VERSION 5.8 ;
BUSBITCHARS "[]" ;
DIVIDERCHAR "/" ;
UNITS
    DATABASE MICRONS 1000 ;
END UNITS

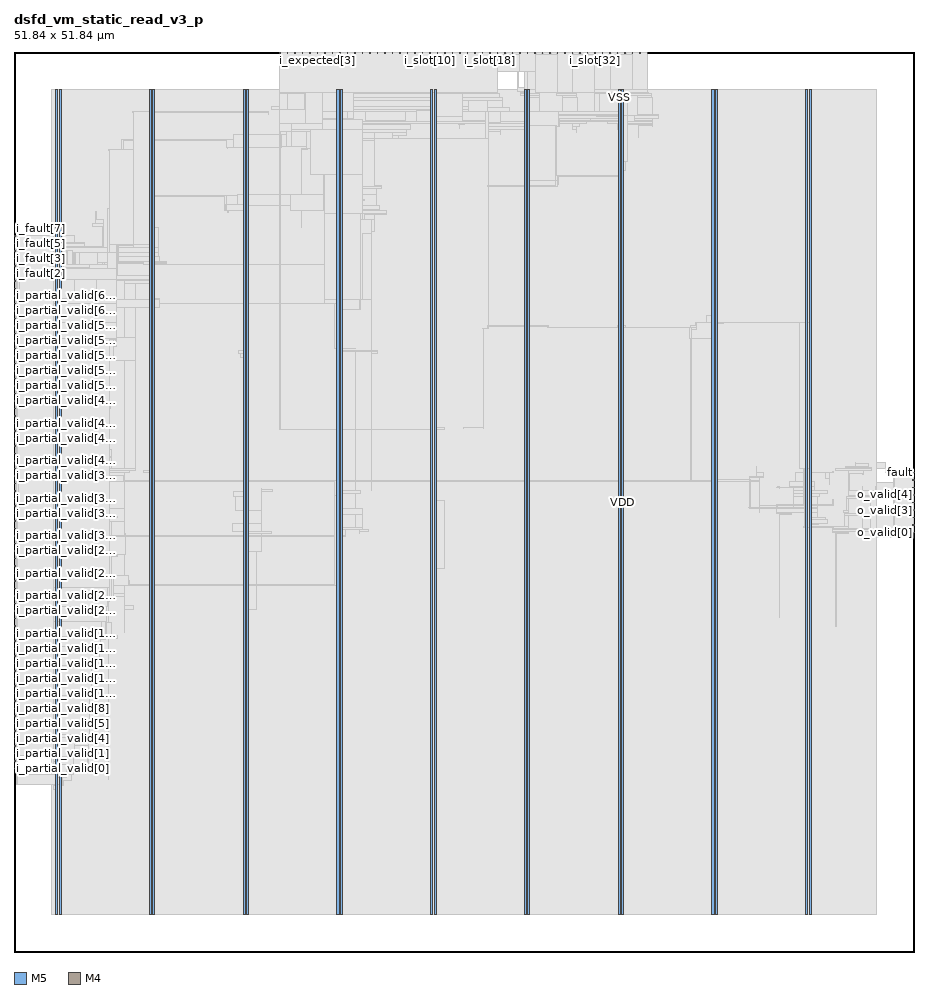
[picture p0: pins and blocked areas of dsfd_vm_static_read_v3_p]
MACRO dsfd_vm_static_read_v3_p
  FOREIGN dsfd_vm_static_read_v3_p 0 0 ;
  CLASS BLOCK ;
  SIZE 51.84 BY 51.84 ;
  PIN ck
    DIRECTION INPUT ;
    USE SIGNAL ;
    PORT
      LAYER M5 ;
        RECT  15.312 51.756 15.336 51.84 ;
    END
  END ck
  PIN fault
    DIRECTION OUTPUT ;
    USE SIGNAL ;
    PORT
      LAYER M4 ;
        RECT  51.756 27.6 51.84 27.624 ;
    END
  END fault
  PIN i_expected[0]
    DIRECTION INPUT ;
    USE SIGNAL ;
    PORT
      LAYER M5 ;
        RECT  16.176 51.756 16.2 51.84 ;
    END
  END i_expected[0]
  PIN i_expected[1]
    DIRECTION INPUT ;
    USE SIGNAL ;
    PORT
      LAYER M5 ;
        RECT  16.608 51.756 16.632 51.84 ;
    END
  END i_expected[1]
  PIN i_expected[2]
    DIRECTION INPUT ;
    USE SIGNAL ;
    PORT
      LAYER M5 ;
        RECT  17.04 51.756 17.064 51.84 ;
    END
  END i_expected[2]
  PIN i_expected[3]
    DIRECTION INPUT ;
    USE SIGNAL ;
    PORT
      LAYER M5 ;
        RECT  17.472 51.756 17.496 51.84 ;
    END
  END i_expected[3]
  PIN i_expected[4]
    DIRECTION INPUT ;
    USE SIGNAL ;
    PORT
      LAYER M5 ;
        RECT  17.904 51.756 17.928 51.84 ;
    END
  END i_expected[4]
  PIN i_expected[5]
    DIRECTION INPUT ;
    USE SIGNAL ;
    PORT
      LAYER M5 ;
        RECT  18.336 51.756 18.36 51.84 ;
    END
  END i_expected[5]
  PIN i_expected[6]
    DIRECTION INPUT ;
    USE SIGNAL ;
    PORT
      LAYER M5 ;
        RECT  18.768 51.756 18.792 51.84 ;
    END
  END i_expected[6]
  PIN i_expected[7]
    DIRECTION INPUT ;
    USE SIGNAL ;
    PORT
      LAYER M5 ;
        RECT  19.2 51.756 19.224 51.84 ;
    END
  END i_expected[7]
  PIN i_fault[0]
    DIRECTION INPUT ;
    USE SIGNAL ;
    PORT
      LAYER M4 ;
        RECT  0 38.208 0.084 38.232 ;
    END
  END i_fault[0]
  PIN i_fault[1]
    DIRECTION INPUT ;
    USE SIGNAL ;
    PORT
      LAYER M4 ;
        RECT  0 38.64 0.084 38.664 ;
    END
  END i_fault[1]
  PIN i_fault[2]
    DIRECTION INPUT ;
    USE SIGNAL ;
    PORT
      LAYER M4 ;
        RECT  0 39.072 0.084 39.096 ;
    END
  END i_fault[2]
  PIN i_fault[3]
    DIRECTION INPUT ;
    USE SIGNAL ;
    PORT
      LAYER M4 ;
        RECT  0 39.504 0.084 39.528 ;
    END
  END i_fault[3]
  PIN i_fault[4]
    DIRECTION INPUT ;
    USE SIGNAL ;
    PORT
      LAYER M4 ;
        RECT  0 39.936 0.084 39.96 ;
    END
  END i_fault[4]
  PIN i_fault[5]
    DIRECTION INPUT ;
    USE SIGNAL ;
    PORT
      LAYER M4 ;
        RECT  0 40.368 0.084 40.392 ;
    END
  END i_fault[5]
  PIN i_fault[6]
    DIRECTION INPUT ;
    USE SIGNAL ;
    PORT
      LAYER M4 ;
        RECT  0 40.8 0.084 40.824 ;
    END
  END i_fault[6]
  PIN i_fault[7]
    DIRECTION INPUT ;
    USE SIGNAL ;
    PORT
      LAYER M4 ;
        RECT  0 41.232 0.084 41.256 ;
    END
  END i_fault[7]
  PIN i_partial_valid[0]
    DIRECTION INPUT ;
    USE SIGNAL ;
    PORT
      LAYER M4 ;
        RECT  0 10.56 0.084 10.584 ;
    END
  END i_partial_valid[0]
  PIN i_partial_valid[10]
    DIRECTION INPUT ;
    USE SIGNAL ;
    PORT
      LAYER M4 ;
        RECT  0 14.88 0.084 14.904 ;
    END
  END i_partial_valid[10]
  PIN i_partial_valid[11]
    DIRECTION INPUT ;
    USE SIGNAL ;
    PORT
      LAYER M4 ;
        RECT  0 15.312 0.084 15.336 ;
    END
  END i_partial_valid[11]
  PIN i_partial_valid[12]
    DIRECTION INPUT ;
    USE SIGNAL ;
    PORT
      LAYER M4 ;
        RECT  0 15.744 0.084 15.768 ;
    END
  END i_partial_valid[12]
  PIN i_partial_valid[13]
    DIRECTION INPUT ;
    USE SIGNAL ;
    PORT
      LAYER M4 ;
        RECT  0 16.176 0.084 16.2 ;
    END
  END i_partial_valid[13]
  PIN i_partial_valid[14]
    DIRECTION INPUT ;
    USE SIGNAL ;
    PORT
      LAYER M4 ;
        RECT  0 16.608 0.084 16.632 ;
    END
  END i_partial_valid[14]
  PIN i_partial_valid[15]
    DIRECTION INPUT ;
    USE SIGNAL ;
    PORT
      LAYER M4 ;
        RECT  0 17.04 0.084 17.064 ;
    END
  END i_partial_valid[15]
  PIN i_partial_valid[16]
    DIRECTION INPUT ;
    USE SIGNAL ;
    PORT
      LAYER M4 ;
        RECT  0 17.472 0.084 17.496 ;
    END
  END i_partial_valid[16]
  PIN i_partial_valid[17]
    DIRECTION INPUT ;
    USE SIGNAL ;
    PORT
      LAYER M4 ;
        RECT  0 17.904 0.084 17.928 ;
    END
  END i_partial_valid[17]
  PIN i_partial_valid[18]
    DIRECTION INPUT ;
    USE SIGNAL ;
    PORT
      LAYER M4 ;
        RECT  0 18.336 0.084 18.36 ;
    END
  END i_partial_valid[18]
  PIN i_partial_valid[19]
    DIRECTION INPUT ;
    USE SIGNAL ;
    PORT
      LAYER M4 ;
        RECT  0 18.768 0.084 18.792 ;
    END
  END i_partial_valid[19]
  PIN i_partial_valid[1]
    DIRECTION INPUT ;
    USE SIGNAL ;
    PORT
      LAYER M4 ;
        RECT  0 10.992 0.084 11.016 ;
    END
  END i_partial_valid[1]
  PIN i_partial_valid[20]
    DIRECTION INPUT ;
    USE SIGNAL ;
    PORT
      LAYER M4 ;
        RECT  0 19.2 0.084 19.224 ;
    END
  END i_partial_valid[20]
  PIN i_partial_valid[21]
    DIRECTION INPUT ;
    USE SIGNAL ;
    PORT
      LAYER M4 ;
        RECT  0 19.632 0.084 19.656 ;
    END
  END i_partial_valid[21]
  PIN i_partial_valid[22]
    DIRECTION INPUT ;
    USE SIGNAL ;
    PORT
      LAYER M4 ;
        RECT  0 20.064 0.084 20.088 ;
    END
  END i_partial_valid[22]
  PIN i_partial_valid[23]
    DIRECTION INPUT ;
    USE SIGNAL ;
    PORT
      LAYER M4 ;
        RECT  0 20.496 0.084 20.52 ;
    END
  END i_partial_valid[23]
  PIN i_partial_valid[24]
    DIRECTION INPUT ;
    USE SIGNAL ;
    PORT
      LAYER M4 ;
        RECT  0 20.928 0.084 20.952 ;
    END
  END i_partial_valid[24]
  PIN i_partial_valid[25]
    DIRECTION INPUT ;
    USE SIGNAL ;
    PORT
      LAYER M4 ;
        RECT  0 21.36 0.084 21.384 ;
    END
  END i_partial_valid[25]
  PIN i_partial_valid[26]
    DIRECTION INPUT ;
    USE SIGNAL ;
    PORT
      LAYER M4 ;
        RECT  0 21.792 0.084 21.816 ;
    END
  END i_partial_valid[26]
  PIN i_partial_valid[27]
    DIRECTION INPUT ;
    USE SIGNAL ;
    PORT
      LAYER M4 ;
        RECT  0 22.224 0.084 22.248 ;
    END
  END i_partial_valid[27]
  PIN i_partial_valid[28]
    DIRECTION INPUT ;
    USE SIGNAL ;
    PORT
      LAYER M4 ;
        RECT  0 22.656 0.084 22.68 ;
    END
  END i_partial_valid[28]
  PIN i_partial_valid[29]
    DIRECTION INPUT ;
    USE SIGNAL ;
    PORT
      LAYER M4 ;
        RECT  0 23.088 0.084 23.112 ;
    END
  END i_partial_valid[29]
  PIN i_partial_valid[2]
    DIRECTION INPUT ;
    USE SIGNAL ;
    PORT
      LAYER M4 ;
        RECT  0 11.424 0.084 11.448 ;
    END
  END i_partial_valid[2]
  PIN i_partial_valid[30]
    DIRECTION INPUT ;
    USE SIGNAL ;
    PORT
      LAYER M4 ;
        RECT  0 23.52 0.084 23.544 ;
    END
  END i_partial_valid[30]
  PIN i_partial_valid[31]
    DIRECTION INPUT ;
    USE SIGNAL ;
    PORT
      LAYER M4 ;
        RECT  0 23.952 0.084 23.976 ;
    END
  END i_partial_valid[31]
  PIN i_partial_valid[32]
    DIRECTION INPUT ;
    USE SIGNAL ;
    PORT
      LAYER M4 ;
        RECT  0 24.384 0.084 24.408 ;
    END
  END i_partial_valid[32]
  PIN i_partial_valid[33]
    DIRECTION INPUT ;
    USE SIGNAL ;
    PORT
      LAYER M4 ;
        RECT  0 24.816 0.084 24.84 ;
    END
  END i_partial_valid[33]
  PIN i_partial_valid[34]
    DIRECTION INPUT ;
    USE SIGNAL ;
    PORT
      LAYER M4 ;
        RECT  0 25.248 0.084 25.272 ;
    END
  END i_partial_valid[34]
  PIN i_partial_valid[35]
    DIRECTION INPUT ;
    USE SIGNAL ;
    PORT
      LAYER M4 ;
        RECT  0 25.68 0.084 25.704 ;
    END
  END i_partial_valid[35]
  PIN i_partial_valid[36]
    DIRECTION INPUT ;
    USE SIGNAL ;
    PORT
      LAYER M4 ;
        RECT  0 26.112 0.084 26.136 ;
    END
  END i_partial_valid[36]
  PIN i_partial_valid[37]
    DIRECTION INPUT ;
    USE SIGNAL ;
    PORT
      LAYER M4 ;
        RECT  0 26.544 0.084 26.568 ;
    END
  END i_partial_valid[37]
  PIN i_partial_valid[38]
    DIRECTION INPUT ;
    USE SIGNAL ;
    PORT
      LAYER M4 ;
        RECT  0 26.976 0.084 27 ;
    END
  END i_partial_valid[38]
  PIN i_partial_valid[39]
    DIRECTION INPUT ;
    USE SIGNAL ;
    PORT
      LAYER M4 ;
        RECT  0 27.408 0.084 27.432 ;
    END
  END i_partial_valid[39]
  PIN i_partial_valid[3]
    DIRECTION INPUT ;
    USE SIGNAL ;
    PORT
      LAYER M4 ;
        RECT  0 11.856 0.084 11.88 ;
    END
  END i_partial_valid[3]
  PIN i_partial_valid[40]
    DIRECTION INPUT ;
    USE SIGNAL ;
    PORT
      LAYER M4 ;
        RECT  0 27.84 0.084 27.864 ;
    END
  END i_partial_valid[40]
  PIN i_partial_valid[41]
    DIRECTION INPUT ;
    USE SIGNAL ;
    PORT
      LAYER M4 ;
        RECT  0 28.272 0.084 28.296 ;
    END
  END i_partial_valid[41]
  PIN i_partial_valid[42]
    DIRECTION INPUT ;
    USE SIGNAL ;
    PORT
      LAYER M4 ;
        RECT  0 28.704 0.084 28.728 ;
    END
  END i_partial_valid[42]
  PIN i_partial_valid[43]
    DIRECTION INPUT ;
    USE SIGNAL ;
    PORT
      LAYER M4 ;
        RECT  0 29.136 0.084 29.16 ;
    END
  END i_partial_valid[43]
  PIN i_partial_valid[44]
    DIRECTION INPUT ;
    USE SIGNAL ;
    PORT
      LAYER M4 ;
        RECT  0 29.568 0.084 29.592 ;
    END
  END i_partial_valid[44]
  PIN i_partial_valid[45]
    DIRECTION INPUT ;
    USE SIGNAL ;
    PORT
      LAYER M4 ;
        RECT  0 30 0.084 30.024 ;
    END
  END i_partial_valid[45]
  PIN i_partial_valid[46]
    DIRECTION INPUT ;
    USE SIGNAL ;
    PORT
      LAYER M4 ;
        RECT  0 30.432 0.084 30.456 ;
    END
  END i_partial_valid[46]
  PIN i_partial_valid[47]
    DIRECTION INPUT ;
    USE SIGNAL ;
    PORT
      LAYER M4 ;
        RECT  0 30.864 0.084 30.888 ;
    END
  END i_partial_valid[47]
  PIN i_partial_valid[48]
    DIRECTION INPUT ;
    USE SIGNAL ;
    PORT
      LAYER M4 ;
        RECT  0 31.296 0.084 31.32 ;
    END
  END i_partial_valid[48]
  PIN i_partial_valid[49]
    DIRECTION INPUT ;
    USE SIGNAL ;
    PORT
      LAYER M4 ;
        RECT  0 31.728 0.084 31.752 ;
    END
  END i_partial_valid[49]
  PIN i_partial_valid[4]
    DIRECTION INPUT ;
    USE SIGNAL ;
    PORT
      LAYER M4 ;
        RECT  0 12.288 0.084 12.312 ;
    END
  END i_partial_valid[4]
  PIN i_partial_valid[50]
    DIRECTION INPUT ;
    USE SIGNAL ;
    PORT
      LAYER M4 ;
        RECT  0 32.16 0.084 32.184 ;
    END
  END i_partial_valid[50]
  PIN i_partial_valid[51]
    DIRECTION INPUT ;
    USE SIGNAL ;
    PORT
      LAYER M4 ;
        RECT  0 32.592 0.084 32.616 ;
    END
  END i_partial_valid[51]
  PIN i_partial_valid[52]
    DIRECTION INPUT ;
    USE SIGNAL ;
    PORT
      LAYER M4 ;
        RECT  0 33.024 0.084 33.048 ;
    END
  END i_partial_valid[52]
  PIN i_partial_valid[53]
    DIRECTION INPUT ;
    USE SIGNAL ;
    PORT
      LAYER M4 ;
        RECT  0 33.456 0.084 33.48 ;
    END
  END i_partial_valid[53]
  PIN i_partial_valid[54]
    DIRECTION INPUT ;
    USE SIGNAL ;
    PORT
      LAYER M4 ;
        RECT  0 33.888 0.084 33.912 ;
    END
  END i_partial_valid[54]
  PIN i_partial_valid[55]
    DIRECTION INPUT ;
    USE SIGNAL ;
    PORT
      LAYER M4 ;
        RECT  0 34.32 0.084 34.344 ;
    END
  END i_partial_valid[55]
  PIN i_partial_valid[56]
    DIRECTION INPUT ;
    USE SIGNAL ;
    PORT
      LAYER M4 ;
        RECT  0 34.752 0.084 34.776 ;
    END
  END i_partial_valid[56]
  PIN i_partial_valid[57]
    DIRECTION INPUT ;
    USE SIGNAL ;
    PORT
      LAYER M4 ;
        RECT  0 35.184 0.084 35.208 ;
    END
  END i_partial_valid[57]
  PIN i_partial_valid[58]
    DIRECTION INPUT ;
    USE SIGNAL ;
    PORT
      LAYER M4 ;
        RECT  0 35.616 0.084 35.64 ;
    END
  END i_partial_valid[58]
  PIN i_partial_valid[59]
    DIRECTION INPUT ;
    USE SIGNAL ;
    PORT
      LAYER M4 ;
        RECT  0 36.048 0.084 36.072 ;
    END
  END i_partial_valid[59]
  PIN i_partial_valid[5]
    DIRECTION INPUT ;
    USE SIGNAL ;
    PORT
      LAYER M4 ;
        RECT  0 12.72 0.084 12.744 ;
    END
  END i_partial_valid[5]
  PIN i_partial_valid[60]
    DIRECTION INPUT ;
    USE SIGNAL ;
    PORT
      LAYER M4 ;
        RECT  0 36.48 0.084 36.504 ;
    END
  END i_partial_valid[60]
  PIN i_partial_valid[61]
    DIRECTION INPUT ;
    USE SIGNAL ;
    PORT
      LAYER M4 ;
        RECT  0 36.912 0.084 36.936 ;
    END
  END i_partial_valid[61]
  PIN i_partial_valid[62]
    DIRECTION INPUT ;
    USE SIGNAL ;
    PORT
      LAYER M4 ;
        RECT  0 37.344 0.084 37.368 ;
    END
  END i_partial_valid[62]
  PIN i_partial_valid[63]
    DIRECTION INPUT ;
    USE SIGNAL ;
    PORT
      LAYER M4 ;
        RECT  0 37.776 0.084 37.8 ;
    END
  END i_partial_valid[63]
  PIN i_partial_valid[6]
    DIRECTION INPUT ;
    USE SIGNAL ;
    PORT
      LAYER M4 ;
        RECT  0 13.152 0.084 13.176 ;
    END
  END i_partial_valid[6]
  PIN i_partial_valid[7]
    DIRECTION INPUT ;
    USE SIGNAL ;
    PORT
      LAYER M4 ;
        RECT  0 13.584 0.084 13.608 ;
    END
  END i_partial_valid[7]
  PIN i_partial_valid[8]
    DIRECTION INPUT ;
    USE SIGNAL ;
    PORT
      LAYER M4 ;
        RECT  0 14.016 0.084 14.04 ;
    END
  END i_partial_valid[8]
  PIN i_partial_valid[9]
    DIRECTION INPUT ;
    USE SIGNAL ;
    PORT
      LAYER M4 ;
        RECT  0 14.448 0.084 14.472 ;
    END
  END i_partial_valid[9]
  PIN i_slot[0]
    DIRECTION INPUT ;
    USE SIGNAL ;
    PORT
      LAYER M5 ;
        RECT  19.632 51.756 19.656 51.84 ;
    END
  END i_slot[0]
  PIN i_slot[10]
    DIRECTION INPUT ;
    USE SIGNAL ;
    PORT
      LAYER M5 ;
        RECT  23.952 51.756 23.976 51.84 ;
    END
  END i_slot[10]
  PIN i_slot[11]
    DIRECTION INPUT ;
    USE SIGNAL ;
    PORT
      LAYER M5 ;
        RECT  24.384 51.756 24.408 51.84 ;
    END
  END i_slot[11]
  PIN i_slot[12]
    DIRECTION INPUT ;
    USE SIGNAL ;
    PORT
      LAYER M5 ;
        RECT  24.816 51.756 24.84 51.84 ;
    END
  END i_slot[12]
  PIN i_slot[13]
    DIRECTION INPUT ;
    USE SIGNAL ;
    PORT
      LAYER M5 ;
        RECT  25.248 51.756 25.272 51.84 ;
    END
  END i_slot[13]
  PIN i_slot[14]
    DIRECTION INPUT ;
    USE SIGNAL ;
    PORT
      LAYER M5 ;
        RECT  25.68 51.756 25.704 51.84 ;
    END
  END i_slot[14]
  PIN i_slot[15]
    DIRECTION INPUT ;
    USE SIGNAL ;
    PORT
      LAYER M5 ;
        RECT  26.112 51.756 26.136 51.84 ;
    END
  END i_slot[15]
  PIN i_slot[16]
    DIRECTION INPUT ;
    USE SIGNAL ;
    PORT
      LAYER M5 ;
        RECT  26.544 51.756 26.568 51.84 ;
    END
  END i_slot[16]
  PIN i_slot[17]
    DIRECTION INPUT ;
    USE SIGNAL ;
    PORT
      LAYER M5 ;
        RECT  26.976 51.756 27 51.84 ;
    END
  END i_slot[17]
  PIN i_slot[18]
    DIRECTION INPUT ;
    USE SIGNAL ;
    PORT
      LAYER M5 ;
        RECT  27.408 51.756 27.432 51.84 ;
    END
  END i_slot[18]
  PIN i_slot[19]
    DIRECTION INPUT ;
    USE SIGNAL ;
    PORT
      LAYER M5 ;
        RECT  27.84 51.756 27.864 51.84 ;
    END
  END i_slot[19]
  PIN i_slot[1]
    DIRECTION INPUT ;
    USE SIGNAL ;
    PORT
      LAYER M5 ;
        RECT  20.064 51.756 20.088 51.84 ;
    END
  END i_slot[1]
  PIN i_slot[20]
    DIRECTION INPUT ;
    USE SIGNAL ;
    PORT
      LAYER M5 ;
        RECT  28.272 51.756 28.296 51.84 ;
    END
  END i_slot[20]
  PIN i_slot[21]
    DIRECTION INPUT ;
    USE SIGNAL ;
    PORT
      LAYER M5 ;
        RECT  28.704 51.756 28.728 51.84 ;
    END
  END i_slot[21]
  PIN i_slot[22]
    DIRECTION INPUT ;
    USE SIGNAL ;
    PORT
      LAYER M5 ;
        RECT  29.136 51.756 29.16 51.84 ;
    END
  END i_slot[22]
  PIN i_slot[23]
    DIRECTION INPUT ;
    USE SIGNAL ;
    PORT
      LAYER M5 ;
        RECT  29.568 51.756 29.592 51.84 ;
    END
  END i_slot[23]
  PIN i_slot[24]
    DIRECTION INPUT ;
    USE SIGNAL ;
    PORT
      LAYER M5 ;
        RECT  30 51.756 30.024 51.84 ;
    END
  END i_slot[24]
  PIN i_slot[25]
    DIRECTION INPUT ;
    USE SIGNAL ;
    PORT
      LAYER M5 ;
        RECT  30.432 51.756 30.456 51.84 ;
    END
  END i_slot[25]
  PIN i_slot[26]
    DIRECTION INPUT ;
    USE SIGNAL ;
    PORT
      LAYER M5 ;
        RECT  30.864 51.756 30.888 51.84 ;
    END
  END i_slot[26]
  PIN i_slot[27]
    DIRECTION INPUT ;
    USE SIGNAL ;
    PORT
      LAYER M5 ;
        RECT  31.296 51.756 31.32 51.84 ;
    END
  END i_slot[27]
  PIN i_slot[28]
    DIRECTION INPUT ;
    USE SIGNAL ;
    PORT
      LAYER M5 ;
        RECT  31.728 51.756 31.752 51.84 ;
    END
  END i_slot[28]
  PIN i_slot[29]
    DIRECTION INPUT ;
    USE SIGNAL ;
    PORT
      LAYER M5 ;
        RECT  32.16 51.756 32.184 51.84 ;
    END
  END i_slot[29]
  PIN i_slot[2]
    DIRECTION INPUT ;
    USE SIGNAL ;
    PORT
      LAYER M5 ;
        RECT  20.496 51.756 20.52 51.84 ;
    END
  END i_slot[2]
  PIN i_slot[30]
    DIRECTION INPUT ;
    USE SIGNAL ;
    PORT
      LAYER M5 ;
        RECT  32.592 51.756 32.616 51.84 ;
    END
  END i_slot[30]
  PIN i_slot[31]
    DIRECTION INPUT ;
    USE SIGNAL ;
    PORT
      LAYER M5 ;
        RECT  33.024 51.756 33.048 51.84 ;
    END
  END i_slot[31]
  PIN i_slot[32]
    DIRECTION INPUT ;
    USE SIGNAL ;
    PORT
      LAYER M5 ;
        RECT  33.456 51.756 33.48 51.84 ;
    END
  END i_slot[32]
  PIN i_slot[33]
    DIRECTION INPUT ;
    USE SIGNAL ;
    PORT
      LAYER M5 ;
        RECT  33.888 51.756 33.912 51.84 ;
    END
  END i_slot[33]
  PIN i_slot[34]
    DIRECTION INPUT ;
    USE SIGNAL ;
    PORT
      LAYER M5 ;
        RECT  34.32 51.756 34.344 51.84 ;
    END
  END i_slot[34]
  PIN i_slot[35]
    DIRECTION INPUT ;
    USE SIGNAL ;
    PORT
      LAYER M5 ;
        RECT  34.752 51.756 34.776 51.84 ;
    END
  END i_slot[35]
  PIN i_slot[36]
    DIRECTION INPUT ;
    USE SIGNAL ;
    PORT
      LAYER M5 ;
        RECT  35.184 51.756 35.208 51.84 ;
    END
  END i_slot[36]
  PIN i_slot[37]
    DIRECTION INPUT ;
    USE SIGNAL ;
    PORT
      LAYER M5 ;
        RECT  35.616 51.756 35.64 51.84 ;
    END
  END i_slot[37]
  PIN i_slot[38]
    DIRECTION INPUT ;
    USE SIGNAL ;
    PORT
      LAYER M5 ;
        RECT  36.048 51.756 36.072 51.84 ;
    END
  END i_slot[38]
  PIN i_slot[39]
    DIRECTION INPUT ;
    USE SIGNAL ;
    PORT
      LAYER M5 ;
        RECT  36.48 51.756 36.504 51.84 ;
    END
  END i_slot[39]
  PIN i_slot[3]
    DIRECTION INPUT ;
    USE SIGNAL ;
    PORT
      LAYER M5 ;
        RECT  20.928 51.756 20.952 51.84 ;
    END
  END i_slot[3]
  PIN i_slot[4]
    DIRECTION INPUT ;
    USE SIGNAL ;
    PORT
      LAYER M5 ;
        RECT  21.36 51.756 21.384 51.84 ;
    END
  END i_slot[4]
  PIN i_slot[5]
    DIRECTION INPUT ;
    USE SIGNAL ;
    PORT
      LAYER M5 ;
        RECT  21.792 51.756 21.816 51.84 ;
    END
  END i_slot[5]
  PIN i_slot[6]
    DIRECTION INPUT ;
    USE SIGNAL ;
    PORT
      LAYER M5 ;
        RECT  22.224 51.756 22.248 51.84 ;
    END
  END i_slot[6]
  PIN i_slot[7]
    DIRECTION INPUT ;
    USE SIGNAL ;
    PORT
      LAYER M5 ;
        RECT  22.656 51.756 22.68 51.84 ;
    END
  END i_slot[7]
  PIN i_slot[8]
    DIRECTION INPUT ;
    USE SIGNAL ;
    PORT
      LAYER M5 ;
        RECT  23.088 51.756 23.112 51.84 ;
    END
  END i_slot[8]
  PIN i_slot[9]
    DIRECTION INPUT ;
    USE SIGNAL ;
    PORT
      LAYER M5 ;
        RECT  23.52 51.756 23.544 51.84 ;
    END
  END i_slot[9]
  PIN o_valid[0]
    DIRECTION OUTPUT ;
    USE SIGNAL ;
    PORT
      LAYER M4 ;
        RECT  51.756 24.144 51.84 24.168 ;
    END
  END o_valid[0]
  PIN o_valid[1]
    DIRECTION OUTPUT ;
    USE SIGNAL ;
    PORT
      LAYER M4 ;
        RECT  51.756 24.576 51.84 24.6 ;
    END
  END o_valid[1]
  PIN o_valid[2]
    DIRECTION OUTPUT ;
    USE SIGNAL ;
    PORT
      LAYER M4 ;
        RECT  51.756 25.008 51.84 25.032 ;
    END
  END o_valid[2]
  PIN o_valid[3]
    DIRECTION OUTPUT ;
    USE SIGNAL ;
    PORT
      LAYER M4 ;
        RECT  51.756 25.44 51.84 25.464 ;
    END
  END o_valid[3]
  PIN o_valid[4]
    DIRECTION OUTPUT ;
    USE SIGNAL ;
    PORT
      LAYER M4 ;
        RECT  51.756 25.872 51.84 25.896 ;
    END
  END o_valid[4]
  PIN o_valid[5]
    DIRECTION OUTPUT ;
    USE SIGNAL ;
    PORT
      LAYER M4 ;
        RECT  51.756 26.304 51.84 26.328 ;
    END
  END o_valid[5]
  PIN o_valid[6]
    DIRECTION OUTPUT ;
    USE SIGNAL ;
    PORT
      LAYER M4 ;
        RECT  51.756 26.736 51.84 26.76 ;
    END
  END o_valid[6]
  PIN o_valid[7]
    DIRECTION OUTPUT ;
    USE SIGNAL ;
    PORT
      LAYER M4 ;
        RECT  51.756 27.168 51.84 27.192 ;
    END
  END o_valid[7]
  PIN rst_n
    DIRECTION INPUT ;
    USE SIGNAL ;
    PORT
      LAYER M5 ;
        RECT  15.744 51.756 15.768 51.84 ;
    END
  END rst_n
  PIN VDD
    DIRECTION INOUT ;
    USE POWER ;
    PORT
      LAYER M5 ;
        RECT  45.792 2.151 45.912 49.689 ;
        RECT  40.392 2.151 40.512 49.689 ;
        RECT  34.992 2.151 35.112 49.689 ;
        RECT  29.592 2.151 29.712 49.689 ;
        RECT  24.192 2.151 24.312 49.689 ;
        RECT  18.792 2.151 18.912 49.689 ;
        RECT  13.392 2.151 13.512 49.689 ;
        RECT  7.992 2.151 8.112 49.689 ;
        RECT  2.592 2.151 2.712 49.689 ;
    END
  END VDD
  PIN VSS
    DIRECTION INOUT ;
    USE GROUND ;
    PORT
      LAYER M5 ;
        RECT  45.6 2.137 45.72 49.703 ;
        RECT  40.2 2.137 40.32 49.703 ;
        RECT  34.8 2.137 34.92 49.703 ;
        RECT  29.4 2.137 29.52 49.703 ;
        RECT  24 2.137 24.12 49.703 ;
        RECT  18.6 2.137 18.72 49.703 ;
        RECT  13.2 2.137 13.32 49.703 ;
        RECT  7.8 2.137 7.92 49.703 ;
        RECT  2.4 2.137 2.52 49.703 ;
    END
  END VSS
  # OT_OBS_CLOSED layer=M5 d_um=1.536 added=48
  OBS
    LAYER RVTN ;
     RECT  2.16 2.16 49.68 2.295 ;
     RECT  2.16 2.565 49.68 2.835 ;
     RECT  2.16 3.105 49.68 3.375 ;
     RECT  2.16 3.645 49.68 3.915 ;
     RECT  2.16 4.185 49.68 4.455 ;
     RECT  2.16 4.725 49.68 4.995 ;
     RECT  2.16 5.265 49.68 5.535 ;
     RECT  2.16 5.805 49.68 6.075 ;
     RECT  2.16 6.345 49.68 6.615 ;
     RECT  2.16 6.885 49.68 7.155 ;
     RECT  2.16 7.425 49.68 7.695 ;
     RECT  2.16 7.965 49.68 8.235 ;
     RECT  2.16 8.505 49.68 8.775 ;
     RECT  2.16 9.045 49.68 9.315 ;
     RECT  2.16 9.585 49.68 9.855 ;
     RECT  2.16 10.125 49.68 10.395 ;
     RECT  2.16 10.665 49.68 10.935 ;
     RECT  2.16 11.205 49.68 11.475 ;
     RECT  2.16 11.745 49.68 12.015 ;
     RECT  2.16 12.285 49.68 12.555 ;
     RECT  2.16 12.825 49.68 13.095 ;
     RECT  2.16 13.365 49.68 13.635 ;
     RECT  2.16 13.905 49.68 14.175 ;
     RECT  2.16 14.445 49.68 14.715 ;
     RECT  2.16 14.985 49.68 15.255 ;
     RECT  2.16 15.525 49.68 15.795 ;
     RECT  2.16 16.065 49.68 16.335 ;
     RECT  2.16 16.605 49.68 16.875 ;
     RECT  2.16 17.145 49.68 17.415 ;
     RECT  2.16 17.685 49.68 17.955 ;
     RECT  2.16 18.225 49.68 18.495 ;
     RECT  2.16 18.765 49.68 19.035 ;
     RECT  2.16 19.305 49.68 19.575 ;
     RECT  2.16 19.845 49.68 20.115 ;
     RECT  2.16 20.385 49.68 20.655 ;
     RECT  2.16 20.925 49.68 21.195 ;
     RECT  2.16 21.465 49.68 21.735 ;
     RECT  2.16 22.005 49.68 22.275 ;
     RECT  2.16 22.545 49.68 22.815 ;
     RECT  2.16 23.085 49.68 23.355 ;
     RECT  2.16 23.625 49.68 23.895 ;
     RECT  2.16 24.165 49.68 24.435 ;
     RECT  2.16 24.705 49.68 24.975 ;
     RECT  2.16 25.245 49.68 25.515 ;
     RECT  2.16 25.785 49.68 26.055 ;
     RECT  2.16 26.325 49.68 26.595 ;
     RECT  2.16 26.865 49.68 27.135 ;
     RECT  2.16 27.405 49.68 27.675 ;
     RECT  2.16 27.945 49.68 28.215 ;
     RECT  2.16 28.485 49.68 28.755 ;
     RECT  2.16 29.025 49.68 29.295 ;
     RECT  2.16 29.565 49.68 29.835 ;
     RECT  2.16 30.105 49.68 30.375 ;
     RECT  2.16 30.645 49.68 30.915 ;
     RECT  2.16 31.185 49.68 31.455 ;
     RECT  2.16 31.725 49.68 31.995 ;
     RECT  2.16 32.265 49.68 32.535 ;
     RECT  2.16 32.805 49.68 33.075 ;
     RECT  2.16 33.345 49.68 33.615 ;
     RECT  2.16 33.885 49.68 34.155 ;
     RECT  2.16 34.425 49.68 34.695 ;
     RECT  2.16 34.965 49.68 35.235 ;
     RECT  2.16 35.505 49.68 35.775 ;
     RECT  2.16 36.045 49.68 36.315 ;
     RECT  2.16 36.585 49.68 36.855 ;
     RECT  2.16 37.125 49.68 37.395 ;
     RECT  2.16 37.665 49.68 37.935 ;
     RECT  2.16 38.205 49.68 38.475 ;
     RECT  2.16 38.745 49.68 39.015 ;
     RECT  2.16 39.285 49.68 39.555 ;
     RECT  2.16 39.825 49.68 40.095 ;
     RECT  2.16 40.365 49.68 40.635 ;
     RECT  2.16 40.905 49.68 41.175 ;
     RECT  2.16 41.445 49.68 41.715 ;
     RECT  2.16 41.985 49.68 42.255 ;
     RECT  2.16 42.525 49.68 42.795 ;
     RECT  2.16 43.065 49.68 43.335 ;
     RECT  2.16 43.605 49.68 43.875 ;
     RECT  2.16 44.145 49.68 44.415 ;
     RECT  2.16 44.685 49.68 44.955 ;
     RECT  2.16 45.225 49.68 45.495 ;
     RECT  2.16 45.765 49.68 46.035 ;
     RECT  2.16 46.305 49.68 46.575 ;
     RECT  2.16 46.845 49.68 47.115 ;
     RECT  2.16 47.385 49.68 47.655 ;
     RECT  2.16 47.925 49.68 48.195 ;
     RECT  2.16 48.465 49.68 48.735 ;
     RECT  2.16 49.005 49.68 49.275 ;
     RECT  2.16 49.545 49.68 49.68 ;
    LAYER RVTP ;
     RECT  2.16 2.295 49.68 2.565 ;
     RECT  2.16 2.835 49.68 3.105 ;
     RECT  2.16 3.375 49.68 3.645 ;
     RECT  2.16 3.915 49.68 4.185 ;
     RECT  2.16 4.455 49.68 4.725 ;
     RECT  2.16 4.995 49.68 5.265 ;
     RECT  2.16 5.535 49.68 5.805 ;
     RECT  2.16 6.075 49.68 6.345 ;
     RECT  2.16 6.615 49.68 6.885 ;
     RECT  2.16 7.155 49.68 7.425 ;
     RECT  2.16 7.695 49.68 7.965 ;
     RECT  2.16 8.235 49.68 8.505 ;
     RECT  2.16 8.775 49.68 9.045 ;
     RECT  2.16 9.315 49.68 9.585 ;
     RECT  2.16 9.855 49.68 10.125 ;
     RECT  2.16 10.395 49.68 10.665 ;
     RECT  2.16 10.935 49.68 11.205 ;
     RECT  2.16 11.475 49.68 11.745 ;
     RECT  2.16 12.015 49.68 12.285 ;
     RECT  2.16 12.555 49.68 12.825 ;
     RECT  2.16 13.095 49.68 13.365 ;
     RECT  2.16 13.635 49.68 13.905 ;
     RECT  2.16 14.175 49.68 14.445 ;
     RECT  2.16 14.715 49.68 14.985 ;
     RECT  2.16 15.255 49.68 15.525 ;
     RECT  2.16 15.795 49.68 16.065 ;
     RECT  2.16 16.335 49.68 16.605 ;
     RECT  2.16 16.875 49.68 17.145 ;
     RECT  2.16 17.415 49.68 17.685 ;
     RECT  2.16 17.955 49.68 18.225 ;
     RECT  2.16 18.495 49.68 18.765 ;
     RECT  2.16 19.035 49.68 19.305 ;
     RECT  2.16 19.575 49.68 19.845 ;
     RECT  2.16 20.115 49.68 20.385 ;
     RECT  2.16 20.655 49.68 20.925 ;
     RECT  2.16 21.195 49.68 21.465 ;
     RECT  2.16 21.735 49.68 22.005 ;
     RECT  2.16 22.275 49.68 22.545 ;
     RECT  2.16 22.815 49.68 23.085 ;
     RECT  2.16 23.355 49.68 23.625 ;
     RECT  2.16 23.895 49.68 24.165 ;
     RECT  2.16 24.435 49.68 24.705 ;
     RECT  2.16 24.975 49.68 25.245 ;
     RECT  2.16 25.515 49.68 25.785 ;
     RECT  2.16 26.055 49.68 26.325 ;
     RECT  2.16 26.595 49.68 26.865 ;
     RECT  2.16 27.135 49.68 27.405 ;
     RECT  2.16 27.675 49.68 27.945 ;
     RECT  2.16 28.215 49.68 28.485 ;
     RECT  2.16 28.755 49.68 29.025 ;
     RECT  2.16 29.295 49.68 29.565 ;
     RECT  2.16 29.835 49.68 30.105 ;
     RECT  2.16 30.375 49.68 30.645 ;
     RECT  2.16 30.915 49.68 31.185 ;
     RECT  2.16 31.455 49.68 31.725 ;
     RECT  2.16 31.995 49.68 32.265 ;
     RECT  2.16 32.535 49.68 32.805 ;
     RECT  2.16 33.075 49.68 33.345 ;
     RECT  2.16 33.615 49.68 33.885 ;
     RECT  2.16 34.155 49.68 34.425 ;
     RECT  2.16 34.695 49.68 34.965 ;
     RECT  2.16 35.235 49.68 35.505 ;
     RECT  2.16 35.775 49.68 36.045 ;
     RECT  2.16 36.315 49.68 36.585 ;
     RECT  2.16 36.855 49.68 37.125 ;
     RECT  2.16 37.395 49.68 37.665 ;
     RECT  2.16 37.935 49.68 38.205 ;
     RECT  2.16 38.475 49.68 38.745 ;
     RECT  2.16 39.015 49.68 39.285 ;
     RECT  2.16 39.555 49.68 39.825 ;
     RECT  2.16 40.095 49.68 40.365 ;
     RECT  2.16 40.635 49.68 40.905 ;
     RECT  2.16 41.175 49.68 41.445 ;
     RECT  2.16 41.715 49.68 41.985 ;
     RECT  2.16 42.255 49.68 42.525 ;
     RECT  2.16 42.795 49.68 43.065 ;
     RECT  2.16 43.335 49.68 43.605 ;
     RECT  2.16 43.875 49.68 44.145 ;
     RECT  2.16 44.415 49.68 44.685 ;
     RECT  2.16 44.955 49.68 45.225 ;
     RECT  2.16 45.495 49.68 45.765 ;
     RECT  2.16 46.035 49.68 46.305 ;
     RECT  2.16 46.575 49.68 46.845 ;
     RECT  2.16 47.115 49.68 47.385 ;
     RECT  2.16 47.655 49.68 47.925 ;
     RECT  2.16 48.195 49.68 48.465 ;
     RECT  2.16 48.735 49.68 49.005 ;
     RECT  2.16 49.275 49.68 49.545 ;
    LAYER M1 ;
     RECT  2.16 2.151 49.68 49.689 ;
    LAYER M2 ;
     RECT  2.16 2.151 49.68 49.689 ;
     RECT  49.68 27.846 50.207 28.206 ;
     RECT  49.68 23.904 50.711 25.47 ;
     RECT  49.68 26.496 50.711 27.054 ;
     RECT  50.207 27.846 50.711 27.864 ;
     RECT  50.711 23.904 50.747 23.922 ;
    LAYER M3 ;
     RECT  2.415 2.143 2.505 2.413 ;
     RECT  7.815 2.143 7.905 2.413 ;
     RECT  13.215 2.143 13.305 2.413 ;
     RECT  18.615 2.143 18.705 2.413 ;
     RECT  24.015 2.143 24.105 2.413 ;
     RECT  29.415 2.143 29.505 2.413 ;
     RECT  34.815 2.143 34.905 2.413 ;
     RECT  40.215 2.143 40.305 2.413 ;
     RECT  45.615 2.143 45.705 2.413 ;
     RECT  2.415 2.413 2.697 8.977 ;
     RECT  2.415 8.977 2.754 9.355 ;
     RECT  2.304 9.355 2.754 9.589 ;
     RECT  2.304 9.589 2.826 9.859 ;
     RECT  2.304 9.859 3.33 10.201 ;
     RECT  2.304 10.201 3.438 10.471 ;
     RECT  2.304 10.471 3.906 10.625 ;
     RECT  2.304 10.625 3.438 10.975 ;
     RECT  2.268 10.975 3.438 11.407 ;
     RECT  4.248 10.741 4.266 11.407 ;
     RECT  2.268 11.407 4.266 11.579 ;
     RECT  2.304 11.579 4.266 11.911 ;
     RECT  2.304 11.911 4.302 12.091 ;
     RECT  2.304 12.091 4.41 12.361 ;
     RECT  5.436 9.931 5.454 12.361 ;
     RECT  2.304 12.361 5.454 18.031 ;
     RECT  2.304 18.031 5.958 18.221 ;
     RECT  2.304 18.221 5.598 18.959 ;
     RECT  6.372 18.391 6.39 19.741 ;
     RECT  13.215 2.413 13.497 19.741 ;
     RECT  6.372 19.741 6.858 19.949 ;
     RECT  2.304 18.959 5.454 20.191 ;
     RECT  2.304 20.191 5.49 20.461 ;
     RECT  6.372 19.949 6.39 20.461 ;
     RECT  2.304 20.461 6.39 20.624 ;
     RECT  7.815 2.413 8.097 21.091 ;
     RECT  2.34 20.624 6.39 21.115 ;
     RECT  7.815 21.091 8.118 21.149 ;
     RECT  2.34 21.115 6.642 21.355 ;
     RECT  2.304 21.355 6.642 21.389 ;
     RECT  2.304 21.389 6.57 21.677 ;
     RECT  24.015 2.413 24.297 22.081 ;
     RECT  2.304 21.677 6.39 22.891 ;
     RECT  13.215 19.741 13.95 23.053 ;
     RECT  18.615 2.413 18.897 23.947 ;
     RECT  2.304 22.891 6.426 23.981 ;
     RECT  49.356 23.935 49.374 24.061 ;
     RECT  6.372 23.981 6.426 24.089 ;
     RECT  13.215 23.053 14.274 24.097 ;
     RECT  47.34 18.769 47.358 24.097 ;
     RECT  47.34 24.097 48.006 24.133 ;
     RECT  47.34 24.133 48.078 24.169 ;
     RECT  50.724 23.899 50.742 24.173 ;
     RECT  13.215 24.097 14.85 24.197 ;
     RECT  13.215 24.197 14.274 24.241 ;
     RECT  19.872 24.097 19.89 24.241 ;
     RECT  47.16 24.169 48.078 24.241 ;
     RECT  49.32 24.061 49.374 24.241 ;
     RECT  18.615 23.947 19.098 24.331 ;
     RECT  19.872 24.241 20.394 24.331 ;
     RECT  18.615 24.331 20.394 24.359 ;
     RECT  47.16 24.241 49.374 24.359 ;
     RECT  47.16 24.359 49.338 24.395 ;
     RECT  18.615 24.359 20.07 24.431 ;
     RECT  45.615 2.413 45.897 24.475 ;
     RECT  47.16 24.395 48.078 24.509 ;
     RECT  45.576 24.475 45.897 24.637 ;
     RECT  12.6 24.241 14.274 24.665 ;
     RECT  45.576 24.637 46.314 24.673 ;
     RECT  2.304 23.981 5.634 24.781 ;
     RECT  6.372 24.089 6.39 24.781 ;
     RECT  45.576 24.673 46.854 24.935 ;
     RECT  45.576 24.935 46.746 25.007 ;
     RECT  47.808 24.509 48.078 25.141 ;
     RECT  48.888 24.395 49.338 25.141 ;
     RECT  18.615 24.431 18.897 25.147 ;
     RECT  47.808 25.141 49.338 25.169 ;
     RECT  18.612 25.147 18.897 25.177 ;
     RECT  19.656 24.431 20.07 25.177 ;
     RECT  44.1 19.273 44.118 25.177 ;
     RECT  18.612 25.177 20.07 25.205 ;
     RECT  47.808 25.169 48.582 25.241 ;
     RECT  44.1 25.177 44.766 25.249 ;
     RECT  43.92 25.249 44.766 25.321 ;
     RECT  45.576 25.007 46.278 25.321 ;
     RECT  47.808 25.241 48.078 25.321 ;
     RECT  13.215 24.665 14.274 25.411 ;
     RECT  12.78 25.411 14.274 25.439 ;
     RECT  47.772 25.321 48.078 25.439 ;
     RECT  2.304 24.781 6.39 25.547 ;
     RECT  18.615 25.205 20.07 25.547 ;
     RECT  42.912 25.321 42.93 25.555 ;
     RECT  43.92 25.321 46.278 25.555 ;
     RECT  42.372 25.555 46.278 25.613 ;
     RECT  42.912 25.613 46.278 25.619 ;
     RECT  42.912 25.619 43.938 25.709 ;
     RECT  43.776 25.709 43.938 25.745 ;
     RECT  43.92 25.745 43.938 25.757 ;
     RECT  0.108 25.675 0.126 25.805 ;
     RECT  24.015 22.081 24.786 25.979 ;
     RECT  47.16 25.723 47.178 26.051 ;
     RECT  47.952 25.439 48.078 26.131 ;
     RECT  49.32 25.169 49.338 26.131 ;
     RECT  47.952 26.131 49.338 26.249 ;
     RECT  12.78 25.439 13.497 26.257 ;
     RECT  44.892 25.619 46.278 26.257 ;
     RECT  48.06 26.249 49.338 26.299 ;
     RECT  18.615 25.547 19.674 26.401 ;
     RECT  44.892 26.257 46.386 26.401 ;
     RECT  12.636 26.257 13.497 26.519 ;
     RECT  14.256 25.439 14.274 26.527 ;
     RECT  18.615 26.401 19.962 26.555 ;
     RECT  44.892 26.401 46.854 26.555 ;
     RECT  48.06 26.299 49.626 26.555 ;
     RECT  2.304 25.547 5.418 26.573 ;
     RECT  48.06 26.555 48.87 26.591 ;
     RECT  14.256 26.527 14.886 26.627 ;
     RECT  2.34 26.573 5.418 26.671 ;
     RECT  14.256 26.627 14.274 26.699 ;
     RECT  44.1 26.671 44.118 26.731 ;
     RECT  43.956 26.731 44.118 26.789 ;
     RECT  49.608 26.555 49.626 26.789 ;
     RECT  44.892 26.555 46.098 26.797 ;
     RECT  48.852 26.591 48.87 26.825 ;
     RECT  2.34 26.671 5.454 26.941 ;
     RECT  44.676 26.797 46.098 27.095 ;
     RECT  42.912 25.709 42.93 27.115 ;
     RECT  42.516 27.115 42.93 27.163 ;
     RECT  46.944 26.941 46.962 27.301 ;
     RECT  42.372 27.163 42.93 27.337 ;
     RECT  2.34 26.941 5.526 27.355 ;
     RECT  6.372 25.547 6.39 27.355 ;
     RECT  42.372 27.337 43.182 27.365 ;
     RECT  48.06 26.591 48.114 27.571 ;
     RECT  48.888 27.481 48.906 27.571 ;
     RECT  46.728 27.301 46.962 27.595 ;
     RECT  50.688 24.571 50.706 27.595 ;
     RECT  46.728 27.595 47.178 27.599 ;
     RECT  2.304 27.355 6.39 27.607 ;
     RECT  7.815 21.149 8.097 27.607 ;
     RECT  42.768 27.365 43.182 27.635 ;
     RECT  45.036 27.095 45.897 27.635 ;
     RECT  47.16 27.599 47.178 27.671 ;
     RECT  48.06 27.571 48.906 27.715 ;
     RECT  7.452 27.607 8.097 27.743 ;
     RECT  2.304 27.607 6.678 27.751 ;
     RECT  47.34 27.715 48.906 27.751 ;
     RECT  2.304 27.751 7.002 27.869 ;
     RECT  47.34 27.751 49.374 27.869 ;
     RECT  50.184 27.595 50.706 27.869 ;
     RECT  47.88 27.869 49.374 27.905 ;
     RECT  42.768 27.635 42.786 27.941 ;
     RECT  47.88 27.905 49.194 27.941 ;
     RECT  48.456 27.941 49.194 28.139 ;
     RECT  48.456 28.139 48.474 28.175 ;
     RECT  50.184 27.869 50.202 28.211 ;
     RECT  2.304 27.869 5.598 28.949 ;
     RECT  24.015 25.979 24.297 30.091 ;
     RECT  24.015 30.091 24.786 30.209 ;
     RECT  25.884 30.181 25.902 30.221 ;
     RECT  2.304 28.949 5.418 31.261 ;
     RECT  2.304 31.261 5.526 31.325 ;
     RECT  2.34 31.325 5.526 31.919 ;
     RECT  2.34 31.919 5.418 32.155 ;
     RECT  2.304 32.155 5.418 34.051 ;
     RECT  6.372 27.869 7.002 34.051 ;
     RECT  13.215 26.519 13.497 34.231 ;
     RECT  13.068 34.231 13.497 34.501 ;
     RECT  20.592 26.599 20.61 34.501 ;
     RECT  18.615 26.555 19.674 34.591 ;
     RECT  20.592 34.501 20.934 34.591 ;
     RECT  18.615 34.591 20.934 34.619 ;
     RECT  12.924 34.501 13.497 34.655 ;
     RECT  2.304 34.051 7.002 35.405 ;
     RECT  38.988 35.323 39.006 35.851 ;
     RECT  34.815 2.413 35.097 35.947 ;
     RECT  38.988 35.851 39.294 35.947 ;
     RECT  30.744 35.947 30.762 36.077 ;
     RECT  34.776 35.947 35.19 36.077 ;
     RECT  38.952 35.947 39.294 36.113 ;
     RECT  40.215 2.413 40.497 36.211 ;
     RECT  39.276 36.113 39.294 36.235 ;
     RECT  40.215 36.211 40.842 36.235 ;
     RECT  39.276 36.235 40.842 36.239 ;
     RECT  39.888 36.239 40.842 36.269 ;
     RECT  2.304 35.405 5.418 36.275 ;
     RECT  39.888 36.269 40.497 36.689 ;
     RECT  2.34 36.275 5.418 37.051 ;
     RECT  7.815 27.743 8.097 37.147 ;
     RECT  18.615 34.619 20.61 37.589 ;
     RECT  7.815 37.147 8.37 37.613 ;
     RECT  18.615 37.589 19.278 37.625 ;
     RECT  2.304 37.051 5.418 37.741 ;
     RECT  6.372 35.405 7.002 38.515 ;
     RECT  7.815 37.613 8.097 38.515 ;
     RECT  2.268 37.741 5.418 38.677 ;
     RECT  6.372 38.515 8.097 38.677 ;
     RECT  2.268 38.677 8.097 38.717 ;
     RECT  2.304 38.717 8.097 38.975 ;
     RECT  18.615 37.625 18.897 39.355 ;
     RECT  2.304 38.975 5.202 39.479 ;
     RECT  0.108 39.499 0.126 39.629 ;
     RECT  18.468 39.355 18.897 39.629 ;
     RECT  5.94 38.975 8.097 39.631 ;
     RECT  5.076 39.479 5.202 39.721 ;
     RECT  5.94 39.631 8.766 39.721 ;
     RECT  5.076 39.721 8.766 39.749 ;
     RECT  2.304 39.479 4.338 40.055 ;
     RECT  5.076 39.749 8.37 40.055 ;
     RECT  2.415 40.055 4.338 40.267 ;
     RECT  5.076 40.055 8.298 40.267 ;
     RECT  2.415 40.267 8.298 40.559 ;
     RECT  2.415 40.559 6.894 40.595 ;
     RECT  2.415 40.595 5.13 40.631 ;
     RECT  5.904 40.595 6.894 40.667 ;
     RECT  5.904 40.667 6.75 40.781 ;
     RECT  2.415 40.631 4.086 40.795 ;
     RECT  6.084 40.781 6.75 40.829 ;
     RECT  2.304 40.795 4.086 40.865 ;
     RECT  2.415 40.865 3.474 41.243 ;
     RECT  20.052 37.589 20.61 41.369 ;
     RECT  20.592 41.369 20.61 41.485 ;
     RECT  2.415 41.243 2.79 41.675 ;
     RECT  7.815 40.559 8.298 41.747 ;
     RECT  6.372 40.829 6.75 41.749 ;
     RECT  7.815 41.747 8.097 41.755 ;
     RECT  5.112 40.631 5.13 41.791 ;
     RECT  6.372 41.749 6.858 41.791 ;
     RECT  6.372 41.791 7.002 41.909 ;
     RECT  7.74 41.755 8.097 41.909 ;
     RECT  4.5 41.791 5.13 41.945 ;
     RECT  4.716 41.945 5.13 42.179 ;
     RECT  20.592 41.485 20.754 42.187 ;
     RECT  20.196 42.187 20.754 42.493 ;
     RECT  18.615 39.629 18.897 42.565 ;
     RECT  20.196 42.493 21.474 42.565 ;
     RECT  6.372 41.909 6.75 42.593 ;
     RECT  4.716 42.179 4.734 42.629 ;
     RECT  18.615 42.565 19.206 42.691 ;
     RECT  20.052 42.565 21.474 42.691 ;
     RECT  12.312 42.601 12.33 42.715 ;
     RECT  16.56 41.719 16.578 42.715 ;
     RECT  12.168 42.715 12.33 42.719 ;
     RECT  18.54 42.691 21.474 42.719 ;
     RECT  12.168 42.719 12.186 42.755 ;
     RECT  6.372 42.593 6.39 42.763 ;
     RECT  18.54 42.719 21.042 42.763 ;
     RECT  18.396 42.763 21.042 42.989 ;
     RECT  15.948 42.715 16.578 43.025 ;
     RECT  16.092 43.025 16.578 43.037 ;
     RECT  6.048 42.763 6.39 43.141 ;
     RECT  13.215 34.655 13.497 43.501 ;
     RECT  12.996 43.501 13.497 43.537 ;
     RECT  5.976 43.141 6.39 43.565 ;
     RECT  12.888 43.537 13.497 43.613 ;
     RECT  18.396 42.989 20.862 43.645 ;
     RECT  17.82 43.645 20.862 43.951 ;
     RECT  17.82 43.951 21.15 44.069 ;
     RECT  20.736 44.069 21.15 44.141 ;
     RECT  30.96 44.107 30.978 44.147 ;
     RECT  31.32 44.221 31.338 44.477 ;
     RECT  34.815 36.077 35.097 45.031 ;
     RECT  17.82 44.069 18.897 45.419 ;
     RECT  34.815 45.031 35.226 45.581 ;
     RECT  6.372 43.565 6.39 46.111 ;
     RECT  17.82 45.419 17.838 46.111 ;
     RECT  6.372 46.111 6.462 46.171 ;
     RECT  6.264 46.171 6.462 46.229 ;
     RECT  16.56 43.037 16.578 46.237 ;
     RECT  16.56 46.237 16.902 46.301 ;
     RECT  17.64 46.111 17.838 46.315 ;
     RECT  18.576 45.419 18.897 46.315 ;
     RECT  12.276 46.309 12.294 46.349 ;
     RECT  17.64 46.315 18.897 46.381 ;
     RECT  15.372 46.315 15.39 46.411 ;
     RECT  15.264 46.411 15.39 46.499 ;
     RECT  16.38 46.381 16.398 46.499 ;
     RECT  15.264 46.499 15.282 46.535 ;
     RECT  17.424 46.381 18.897 46.651 ;
     RECT  19.944 44.069 19.962 46.651 ;
     RECT  13.215 43.613 13.497 46.741 ;
     RECT  17.424 46.651 19.962 46.741 ;
     RECT  20.736 44.141 20.754 46.741 ;
     RECT  6.192 46.381 6.21 46.781 ;
     RECT  21.78 46.843 21.798 46.885 ;
     RECT  21.78 46.885 22.158 47.011 ;
     RECT  12.672 46.741 13.497 47.069 ;
     RECT  17.424 46.741 20.754 47.191 ;
     RECT  21.78 47.011 22.59 47.191 ;
     RECT  27.18 46.843 27.198 47.281 ;
     RECT  28.008 47.083 28.026 47.281 ;
     RECT  17.424 47.191 22.59 47.389 ;
     RECT  27.18 47.281 28.026 47.389 ;
     RECT  29.415 2.413 29.697 47.389 ;
     RECT  32.4 47.191 32.418 47.389 ;
     RECT  34.815 45.581 35.097 47.389 ;
     RECT  15.984 47.275 16.002 47.425 ;
     RECT  32.148 47.389 32.418 47.551 ;
     RECT  27.18 47.389 29.697 47.563 ;
     RECT  35.964 46.921 35.982 47.587 ;
     RECT  36.756 47.551 36.774 47.587 ;
     RECT  35.964 47.587 36.774 47.65 ;
     RECT  17.424 47.389 22.842 47.659 ;
     RECT  25.668 47.461 25.686 47.659 ;
     RECT  34.776 47.389 35.097 47.659 ;
     RECT  35.928 47.65 36.774 47.659 ;
     RECT  15.624 47.425 16.002 47.695 ;
     RECT  17.208 47.659 22.842 47.695 ;
     RECT  25.596 47.659 25.938 47.695 ;
     RECT  32.148 47.551 32.598 47.695 ;
     RECT  15.624 47.695 16.146 47.731 ;
     RECT  17.028 47.695 22.842 47.731 ;
     RECT  24.015 30.209 24.297 47.731 ;
     RECT  25.596 47.695 26.334 47.731 ;
     RECT  27.18 47.563 30.114 47.731 ;
     RECT  31.392 47.563 31.41 47.731 ;
     RECT  32.148 47.695 32.814 47.731 ;
     RECT  34.776 47.659 36.774 47.731 ;
     RECT  15.624 47.731 16.29 47.821 ;
     RECT  17.028 47.731 30.114 47.821 ;
     RECT  31.392 47.731 32.994 47.821 ;
     RECT  34.2 47.731 36.774 47.821 ;
     RECT  15.624 47.821 30.294 47.849 ;
     RECT  27.144 47.849 30.294 47.885 ;
     RECT  31.392 47.821 36.774 47.893 ;
     RECT  31.212 47.893 36.774 48.001 ;
     RECT  15.624 47.849 26.334 48.119 ;
     RECT  27.252 47.885 30.294 48.119 ;
     RECT  31.212 48.001 37.134 48.173 ;
     RECT  27.252 48.119 28.602 48.191 ;
     RECT  29.415 48.119 30.294 48.235 ;
     RECT  31.212 48.173 35.097 48.235 ;
     RECT  35.892 48.173 37.134 48.263 ;
     RECT  29.415 48.235 35.097 48.389 ;
     RECT  15.624 48.119 26.154 48.397 ;
     RECT  31.32 48.389 32.454 48.413 ;
     RECT  14.652 48.235 14.67 48.425 ;
     RECT  15.48 48.397 26.154 48.541 ;
     RECT  27.252 48.191 28.53 48.659 ;
     RECT  14.832 48.541 26.154 48.695 ;
     RECT  15.624 48.695 26.154 49.045 ;
     RECT  27.252 48.659 28.134 49.045 ;
     RECT  15.624 49.045 28.134 49.199 ;
     RECT  29.415 48.389 30.294 49.199 ;
     RECT  31.572 48.413 32.454 49.199 ;
     RECT  35.892 48.263 36.774 49.199 ;
     RECT  34.815 48.389 35.097 49.315 ;
     RECT  29.415 49.199 30.258 49.351 ;
     RECT  31.572 49.199 32.418 49.351 ;
     RECT  34.56 49.315 35.097 49.351 ;
     RECT  35.892 49.199 36.738 49.351 ;
     RECT  2.415 41.675 2.697 49.427 ;
     RECT  7.815 41.909 8.097 49.427 ;
     RECT  13.215 47.069 13.497 49.427 ;
     RECT  40.215 36.689 40.497 49.427 ;
     RECT  45.615 27.635 45.897 49.427 ;
     RECT  15.624 49.199 27.954 49.469 ;
     RECT  29.196 49.351 30.258 49.469 ;
     RECT  31.248 49.351 32.418 49.469 ;
     RECT  34.56 49.351 36.738 49.469 ;
     RECT  33.408 48.389 33.75 49.477 ;
     RECT  34.56 49.469 36.558 49.477 ;
     RECT  15.696 49.469 27.738 49.505 ;
     RECT  15.804 49.505 27.738 49.517 ;
     RECT  29.196 49.469 30.078 49.517 ;
     RECT  31.248 49.469 32.238 49.517 ;
     RECT  33.408 49.477 36.558 49.517 ;
     RECT  33.408 49.517 33.534 49.531 ;
     RECT  33.228 49.531 33.534 49.541 ;
     RECT  29.196 49.517 29.61 49.549 ;
     RECT  15.804 49.517 16.146 49.565 ;
     RECT  15.804 49.565 15.822 49.577 ;
     RECT  16.92 49.517 26.01 49.577 ;
     RECT  26.856 49.517 27.738 49.577 ;
     RECT  31.068 49.531 31.086 49.577 ;
     RECT  33.228 49.541 33.246 49.577 ;
     RECT  34.815 49.517 35.406 49.577 ;
     RECT  2.415 49.427 2.505 49.697 ;
     RECT  7.815 49.427 7.905 49.697 ;
     RECT  13.215 49.427 13.305 49.697 ;
     RECT  23.832 49.577 24.105 49.697 ;
     RECT  34.815 49.577 34.905 49.697 ;
     RECT  40.215 49.427 40.305 49.697 ;
     RECT  45.615 49.427 45.705 49.697 ;
     RECT  18.216 49.577 18.774 49.805 ;
     RECT  29.016 49.549 29.61 49.805 ;
     RECT  27.288 49.577 27.306 50.189 ;
     RECT  18.216 49.805 18.234 50.765 ;
     RECT  22.104 49.577 22.122 50.765 ;
     RECT  23.832 49.697 23.85 50.765 ;
     RECT  25.452 49.577 26.01 50.765 ;
     RECT  29.016 49.805 29.034 50.765 ;
    LAYER M4 ;
     RECT  0.06 10.56 0.133 41.256 ;
     RECT  0.133 9.648 0.227 41.256 ;
     RECT  0.227 11.328 2.293 41.256 ;
     RECT  0.227 9.648 2.408 10.2 ;
     RECT  2.293 11.232 2.408 41.256 ;
     RECT  2.408 2.148 2.512 49.692 ;
     RECT  2.512 2.418 2.704 49.422 ;
     RECT  2.704 9.648 2.801 41.256 ;
     RECT  2.801 9.648 2.819 40.392 ;
     RECT  2.819 10.08 3.011 40.392 ;
     RECT  3.011 10.176 3.089 40.392 ;
     RECT  3.089 10.8 3.341 40.392 ;
     RECT  3.341 10.8 3.449 40.296 ;
     RECT  3.449 11.28 3.485 40.296 ;
     RECT  3.485 11.28 3.491 16.008 ;
     RECT  3.491 12 3.521 16.008 ;
     RECT  3.485 16.992 3.539 40.296 ;
     RECT  3.539 17.088 3.773 40.296 ;
     RECT  3.521 12.384 3.917 16.008 ;
     RECT  3.773 17.088 3.953 37.656 ;
     RECT  3.953 17.088 3.971 36.504 ;
     RECT  3.917 12.384 4.019 13.656 ;
     RECT  3.917 14.784 4.025 16.008 ;
     RECT  3.953 37.632 4.025 37.656 ;
     RECT  4.019 12.384 4.163 12.552 ;
     RECT  3.971 17.088 4.211 35.928 ;
     RECT  4.019 13.632 4.252 13.656 ;
     RECT  4.211 17.088 4.313 35.352 ;
     RECT  4.163 12.528 4.355 12.552 ;
     RECT  4.025 15.984 4.355 16.008 ;
     RECT  4.025 14.784 4.457 14.808 ;
     RECT  4.313 31.296 4.457 35.352 ;
     RECT  4.313 17.088 4.601 30.072 ;
     RECT  4.457 31.296 4.601 35.256 ;
     RECT  4.601 17.088 4.637 30.024 ;
     RECT  4.637 17.568 4.643 30.024 ;
     RECT  4.643 17.568 4.781 27.432 ;
     RECT  4.7 16.416 4.787 16.536 ;
     RECT  4.643 28.512 4.817 30.024 ;
     RECT  3.773 38.688 4.825 40.296 ;
     RECT  4.825 38.688 4.925 38.76 ;
     RECT  4.787 16.512 4.931 16.536 ;
     RECT  4.781 17.616 4.979 27.432 ;
     RECT  4.979 18 4.997 27.432 ;
     RECT  4.601 31.296 5.027 32.52 ;
     RECT  4.817 28.512 5.232 29.688 ;
     RECT  4.997 18 5.249 25.656 ;
     RECT  5.249 18.192 5.315 22.824 ;
     RECT  5.249 23.904 5.321 25.656 ;
     RECT  5.321 23.904 5.363 25.272 ;
     RECT  5.363 23.952 5.365 25.272 ;
     RECT  5.232 29.664 5.393 29.688 ;
     RECT  4.601 33.504 5.393 35.256 ;
     RECT  5.315 19.92 5.411 22.824 ;
     RECT  5.027 31.296 5.411 32.088 ;
     RECT  5.365 25.008 5.429 25.272 ;
     RECT  5.393 34.176 5.465 35.256 ;
     RECT  4.925 38.736 5.465 38.76 ;
     RECT  5.411 20.208 5.501 22.824 ;
     RECT  5.411 31.296 5.537 31.464 ;
     RECT  5.501 20.496 5.609 22.824 ;
     RECT  5.232 28.512 5.609 28.536 ;
     RECT  5.465 34.224 5.717 35.256 ;
     RECT  5.609 20.496 5.753 21.672 ;
     RECT  5.717 34.896 5.845 35.256 ;
     RECT  5.845 37.152 5.893 37.176 ;
     RECT  4.825 39.744 5.893 40.296 ;
     RECT  5.845 34.896 5.897 35.4 ;
     RECT  5.897 35.376 5.932 35.4 ;
     RECT  5.365 42.768 5.965 42.792 ;
     RECT  5.315 18.192 5.969 18.216 ;
     RECT  5.609 22.8 5.969 22.824 ;
     RECT  5.429 25.056 5.969 25.08 ;
     RECT  5.893 39.12 5.98 40.776 ;
     RECT  5.98 39.744 5.997 40.776 ;
     RECT  5.965 42.768 6.077 43.56 ;
     RECT  5.461 46.176 6.181 46.2 ;
     RECT  4.997 27.12 6.293 27.432 ;
     RECT  6.181 46.176 6.293 46.776 ;
     RECT  5.753 21.12 6.581 21.672 ;
     RECT  6.581 21.12 6.653 21.336 ;
     RECT  5.997 39.744 7.477 39.768 ;
     RECT  6.653 21.12 7.808 21.144 ;
     RECT  5.365 23.952 7.808 23.976 ;
     RECT  6.293 27.12 7.808 27.144 ;
     RECT  5.893 37.152 7.808 37.608 ;
     RECT  7.477 39.6 7.808 39.768 ;
     RECT  5.997 40.752 7.808 40.776 ;
     RECT  6.829 41.76 7.808 41.784 ;
     RECT  6.077 43.536 7.808 43.56 ;
     RECT  6.293 46.752 7.808 46.776 ;
     RECT  6.853 48.384 7.808 48.408 ;
     RECT  7.808 2.148 7.912 49.692 ;
     RECT  7.912 2.418 8.104 49.422 ;
     RECT  8.104 37.152 8.381 37.608 ;
     RECT  8.104 43.536 12.14 43.56 ;
     RECT  12.14 42.72 12.227 43.56 ;
     RECT  8.104 46.752 12.265 46.776 ;
     RECT  12.265 46.32 12.661 46.776 ;
     RECT  12.227 43.008 12.877 43.56 ;
     RECT  8.104 21.12 13.208 21.144 ;
     RECT  8.104 23.952 13.208 23.976 ;
     RECT  8.104 27.12 13.208 27.144 ;
     RECT  8.381 37.344 13.208 37.368 ;
     RECT  8.104 39.6 13.208 39.624 ;
     RECT  12.877 43.008 13.208 43.608 ;
     RECT  12.661 46.32 13.208 47.064 ;
     RECT  8.104 48.384 13.208 48.408 ;
     RECT  13.208 2.148 13.312 49.692 ;
     RECT  13.312 2.418 13.504 49.422 ;
     RECT  13.504 48.384 14.681 48.408 ;
     RECT  13.504 46.32 15.401 47.064 ;
     RECT  15.401 46.416 15.685 47.064 ;
     RECT  13.504 43.008 15.937 43.608 ;
     RECT  15.685 46.416 15.971 48.504 ;
     RECT  16.117 49.536 16.597 49.56 ;
     RECT  16.597 49.488 16.7 49.56 ;
     RECT  16.7 48.864 16.787 49.56 ;
     RECT  15.971 46.416 16.873 47.736 ;
     RECT  16.873 46.272 17.123 47.736 ;
     RECT  15.937 42.72 17.852 43.608 ;
     RECT  17.077 44.784 17.852 44.808 ;
     RECT  18.205 50.736 18.371 50.76 ;
     RECT  13.504 39.6 18.457 39.624 ;
     RECT  13.504 27.12 18.469 27.144 ;
     RECT  13.504 21.12 18.608 21.144 ;
     RECT  13.504 23.952 18.608 23.976 ;
     RECT  18.469 25.152 18.608 25.176 ;
     RECT  18.469 26.256 18.608 27.144 ;
     RECT  15.301 30.096 18.608 30.12 ;
     RECT  18.469 34.752 18.608 34.776 ;
     RECT  13.504 37.344 18.608 37.368 ;
     RECT  18.457 39.36 18.608 39.624 ;
     RECT  17.852 42.72 18.608 44.808 ;
     RECT  17.123 46.32 18.608 47.736 ;
     RECT  16.787 49.008 18.608 49.56 ;
     RECT  18.608 2.148 18.712 49.692 ;
     RECT  18.712 2.418 18.716 49.692 ;
     RECT  18.716 2.418 18.803 49.8 ;
     RECT  18.803 2.418 18.904 49.56 ;
     RECT  18.904 23.952 19.109 23.976 ;
     RECT  18.904 46.848 19.145 48.408 ;
     RECT  18.904 37.584 19.333 37.608 ;
     RECT  18.904 34.752 19.649 34.776 ;
     RECT  18.904 42.72 19.865 43.896 ;
     RECT  19.865 42.72 19.909 43.32 ;
     RECT  19.897 37.008 19.981 37.032 ;
     RECT  19.909 42.192 20.099 43.32 ;
     RECT  20.099 43.296 20.189 43.32 ;
     RECT  20.099 42.192 20.225 42.216 ;
     RECT  19.145 47.856 20.261 48.408 ;
     RECT  22.093 50.736 22.259 50.76 ;
     RECT  20.261 47.904 22.561 48.408 ;
     RECT  22.561 47.856 23.209 48.408 ;
     RECT  23.821 50.736 23.987 50.76 ;
     RECT  18.904 27.12 24.008 27.144 ;
     RECT  18.904 30.096 24.008 30.12 ;
     RECT  19.145 46.848 24.008 46.872 ;
     RECT  23.209 47.856 24.008 48.456 ;
     RECT  18.904 49.536 24.008 49.56 ;
     RECT  24.008 2.148 24.112 49.692 ;
     RECT  24.112 2.418 24.304 49.56 ;
     RECT  24.304 30.096 24.797 30.12 ;
     RECT  24.304 47.904 25.085 48.456 ;
     RECT  24.304 49.536 25.283 49.56 ;
     RECT  25.085 47.904 25.772 48.408 ;
     RECT  25.772 47.856 25.859 48.408 ;
     RECT  26.101 49.488 26.201 49.512 ;
     RECT  25.441 50.736 26.579 50.76 ;
     RECT  25.873 30.192 27.059 30.216 ;
     RECT  24.304 46.848 27.133 46.872 ;
     RECT  25.859 47.904 27.133 48.408 ;
     RECT  26.845 49.536 27.277 49.56 ;
     RECT  27.013 35.904 27.301 35.928 ;
     RECT  27.301 35.904 27.347 36.072 ;
     RECT  27.133 46.848 27.347 48.408 ;
     RECT  27.277 49.536 27.443 50.184 ;
     RECT  27.443 49.536 27.875 49.56 ;
     RECT  27.347 47.76 28.001 48.408 ;
     RECT  29.005 50.736 29.171 50.76 ;
     RECT  24.304 27.12 29.408 27.144 ;
     RECT  27.347 36.048 29.408 36.072 ;
     RECT  27.301 44.112 29.408 44.136 ;
     RECT  28.001 47.856 29.408 48.408 ;
     RECT  29.408 2.148 29.512 49.692 ;
     RECT  29.512 2.418 29.557 49.692 ;
     RECT  29.557 2.418 29.644 49.8 ;
     RECT  29.644 2.418 29.704 49.512 ;
     RECT  29.704 49.488 30.089 49.512 ;
     RECT  29.704 36.048 30.733 36.072 ;
     RECT  30.733 35.952 30.773 36.072 ;
     RECT  29.704 44.112 31.189 44.136 ;
     RECT  31.189 44.112 31.285 44.472 ;
     RECT  31.285 44.112 31.331 44.712 ;
     RECT  31.057 49.536 31.331 49.56 ;
     RECT  31.331 44.448 31.349 44.712 ;
     RECT  29.704 47.568 31.349 48.408 ;
     RECT  31.349 47.568 31.421 48.024 ;
     RECT  31.717 49.488 32.249 49.512 ;
     RECT  31.421 47.904 33.185 48.024 ;
     RECT  33.217 49.536 33.491 49.56 ;
     RECT  30.773 35.952 34.765 35.976 ;
     RECT  29.704 27.12 34.808 27.144 ;
     RECT  34.765 35.952 34.808 36.072 ;
     RECT  31.349 44.688 34.808 44.712 ;
     RECT  33.577 48.144 34.808 48.168 ;
     RECT  33.877 49.488 34.808 49.512 ;
     RECT  34.808 2.148 34.912 49.692 ;
     RECT  34.912 2.418 35.104 49.56 ;
     RECT  35.104 35.952 35.201 36.072 ;
     RECT  35.104 45.552 35.363 45.576 ;
     RECT  35.104 49.488 35.651 49.56 ;
     RECT  35.104 47.856 35.741 48.168 ;
     RECT  35.741 47.856 36.173 47.88 ;
     RECT  35.651 49.488 36.569 49.512 ;
     RECT  35.201 35.952 38.933 35.976 ;
     RECT  35.104 27.12 38.965 27.144 ;
     RECT  38.933 35.328 39.017 35.976 ;
     RECT  38.965 27.12 40.208 27.192 ;
     RECT  39.877 36.24 40.208 36.264 ;
     RECT  40.208 2.148 40.312 49.692 ;
     RECT  40.312 2.418 40.504 49.422 ;
     RECT  40.504 27.12 42.419 27.192 ;
     RECT  42.419 27.12 42.545 27.144 ;
     RECT  42.312 25.584 43.909 25.608 ;
     RECT  43.909 25.584 43.949 25.752 ;
     RECT  43.949 25.728 45.493 25.752 ;
     RECT  43.945 26.736 45.493 26.76 ;
     RECT  45.253 27.888 45.493 27.912 ;
     RECT  45.493 24.48 45.608 24.504 ;
     RECT  45.493 25.728 45.608 27.912 ;
     RECT  40.504 36.24 45.608 36.264 ;
     RECT  45.608 2.148 45.712 49.692 ;
     RECT  45.712 2.418 45.904 49.422 ;
     RECT  45.904 24.48 47.189 24.504 ;
     RECT  45.904 25.728 47.189 25.752 ;
     RECT  45.904 27.6 47.189 27.624 ;
     RECT  49.597 26.304 50.677 26.328 ;
     RECT  50.173 27.6 50.677 27.624 ;
     RECT  50.677 24.576 50.713 27.624 ;
     RECT  50.713 24.144 51.804 27.624 ;
    LAYER M5 ;
     RECT  2.4 2.137 2.52 2.151 ;
     RECT  7.8 2.137 7.92 2.151 ;
     RECT  13.2 2.137 13.32 2.151 ;
     RECT  18.6 2.137 18.72 2.151 ;
     RECT  24 2.137 24.12 2.151 ;
     RECT  29.4 2.137 29.52 2.151 ;
     RECT  34.8 2.137 34.92 2.151 ;
     RECT  40.2 2.137 40.32 2.151 ;
     RECT  45.6 2.137 45.72 2.151 ;
     RECT  2.4 2.151 2.712 9.637 ;
     RECT  2.4 9.637 2.808 10.069 ;
     RECT  0.144 9.637 0.168 10.165 ;
     RECT  2.4 10.069 3 10.789 ;
     RECT  0.144 10.165 0.216 11.027 ;
     RECT  2.4 10.789 3.432 11.221 ;
     RECT  2.304 11.221 3.432 11.269 ;
     RECT  2.304 11.269 3.48 12.373 ;
     RECT  2.304 12.373 4.152 12.517 ;
     RECT  0.144 11.027 0.168 13.715 ;
     RECT  2.304 12.517 4.344 14.773 ;
     RECT  2.304 14.773 4.44 16.405 ;
     RECT  2.304 16.405 4.776 16.501 ;
     RECT  2.304 16.501 4.92 17.605 ;
     RECT  0.144 15.301 0.168 17.699 ;
     RECT  2.304 17.605 4.968 18.181 ;
     RECT  0.144 18.757 0.168 18.899 ;
     RECT  2.304 18.181 5.016 19.045 ;
     RECT  2.304 19.045 5.304 19.909 ;
     RECT  2.304 19.909 5.4 21.013 ;
     RECT  18.6 2.151 18.912 21.109 ;
     RECT  0.144 20.485 0.168 21.683 ;
     RECT  0.144 22.645 0.168 22.835 ;
     RECT  45.6 2.151 45.912 24.469 ;
     RECT  0.144 23.941 0.168 25.139 ;
     RECT  0.288 25.237 0.312 25.715 ;
     RECT  18.48 21.109 18.912 26.291 ;
     RECT  0.144 26.101 0.168 27.109 ;
     RECT  42.384 25.573 42.408 27.203 ;
     RECT  0.144 27.109 0.264 27.443 ;
     RECT  45.504 24.469 45.912 27.877 ;
     RECT  0.144 27.443 0.168 28.547 ;
     RECT  0.144 29.557 0.168 30.275 ;
     RECT  0.144 31.717 0.168 31.955 ;
     RECT  0.144 33.013 0.168 34.165 ;
     RECT  0.144 34.165 0.216 34.355 ;
     RECT  18.6 26.291 18.912 34.741 ;
     RECT  38.976 27.157 39 35.363 ;
     RECT  2.304 21.013 5.496 35.365 ;
     RECT  27.024 30.181 27.048 35.893 ;
     RECT  27.024 35.893 27.336 35.939 ;
     RECT  2.304 35.365 5.88 36.275 ;
     RECT  45.264 27.877 45.912 36.275 ;
     RECT  0.144 34.355 0.168 37.091 ;
     RECT  18.48 34.741 18.912 37.333 ;
     RECT  2.4 36.275 5.88 37.381 ;
     RECT  2.304 37.381 5.88 37.573 ;
     RECT  17.904 37.333 18.912 37.573 ;
     RECT  19.92 36.997 19.944 37.573 ;
     RECT  2.304 37.573 5.928 37.667 ;
     RECT  2.304 37.667 3.48 38.725 ;
     RECT  4.752 37.667 5.928 38.725 ;
     RECT  2.304 38.725 5.928 39.395 ;
     RECT  2.4 39.395 3.048 39.443 ;
     RECT  0.288 38.197 0.312 39.539 ;
     RECT  2.4 39.443 2.856 39.587 ;
     RECT  4.32 39.395 4.344 39.587 ;
     RECT  5.376 39.395 5.928 40.307 ;
     RECT  7.8 2.151 8.112 40.741 ;
     RECT  17.904 37.573 19.944 42.565 ;
     RECT  5.376 40.307 5.496 42.803 ;
     RECT  12.192 42.709 12.216 43.043 ;
     RECT  31.296 44.101 31.32 44.437 ;
     RECT  31.2 44.437 31.32 44.723 ;
     RECT  17.904 42.565 20.088 44.773 ;
     RECT  34.8 2.151 35.112 45.541 ;
     RECT  5.472 42.803 5.496 46.211 ;
     RECT  27.312 35.939 27.336 46.883 ;
     RECT  15.312 30.085 15.336 47.269 ;
     RECT  17.088 44.773 20.088 47.363 ;
     RECT  31.2 44.723 31.224 47.603 ;
     RECT  15.312 47.269 15.96 47.701 ;
     RECT  17.76 47.363 20.088 47.939 ;
     RECT  17.76 47.939 19.56 48.035 ;
     RECT  25.824 47.845 25.848 48.131 ;
     RECT  34.8 45.541 35.352 48.179 ;
     RECT  6.864 40.741 8.112 48.419 ;
     RECT  17.76 48.035 19.224 48.419 ;
     RECT  15.312 47.701 16.776 48.515 ;
     RECT  15.312 48.515 15.768 49.477 ;
     RECT  16.752 48.515 16.776 49.477 ;
     RECT  29.4 2.151 29.712 49.477 ;
     RECT  34.8 48.179 35.112 49.477 ;
     RECT  15.312 49.477 16.776 49.525 ;
     RECT  17.76 48.419 18.912 49.525 ;
     RECT  24 2.151 24.312 49.525 ;
     RECT  26.112 49.477 26.136 49.525 ;
     RECT  31.728 49.477 32.184 49.525 ;
     RECT  33.888 49.477 36.504 49.525 ;
     RECT  2.4 39.587 2.712 49.689 ;
     RECT  7.8 48.419 8.112 49.689 ;
     RECT  13.2 2.151 13.512 49.689 ;
     RECT  40.2 2.151 40.512 49.689 ;
     RECT  45.6 36.275 45.912 49.689 ;
     RECT  2.4 49.689 2.52 49.703 ;
     RECT  7.8 49.689 7.92 49.703 ;
     RECT  13.2 49.689 13.32 49.703 ;
     RECT  29.4 49.477 30.024 49.703 ;
     RECT  33.456 49.525 36.504 49.703 ;
     RECT  40.2 49.689 40.32 49.703 ;
     RECT  45.6 49.689 45.72 49.703 ;
     RECT  29.568 49.703 30.024 50.725 ;
     RECT  15.312 49.525 27.864 51.792 ;
     RECT  29.136 50.725 30.024 51.792 ;
     RECT  31.296 49.525 32.184 51.792 ;
     RECT  33.456 49.703 34.344 51.792 ;
     RECT  35.616 49.703 36.504 51.792 ;
     RECT  0.144 17.699 0.168 18.757 ;
     RECT  0.144 21.683 0.168 22.645 ;
     RECT  0.144 22.835 0.168 23.941 ;
     RECT  0.144 25.139 0.168 25.237 ;
     RECT  0.144 25.237 0.288 25.715 ;
     RECT  0.144 25.715 0.264 26.101 ;
     RECT  0.168 26.101 0.264 27.109 ;
     RECT  39 27.157 40.2 35.363 ;
     RECT  0.144 28.547 0.168 29.557 ;
     RECT  0.144 30.275 0.168 31.717 ;
     RECT  0.144 31.955 0.168 33.013 ;
     RECT  2.304 36.275 2.4 37.381 ;
     RECT  18.912 36.997 19.92 37.573 ;
     RECT  3.48 37.667 4.752 38.725 ;
     RECT  3.048 39.395 4.32 39.443 ;
     RECT  4.344 39.395 5.376 39.587 ;
     RECT  2.856 39.443 4.32 39.587 ;
     RECT  5.496 40.307 5.928 40.741 ;
     RECT  5.496 40.741 6.864 46.211 ;
     RECT  12.216 42.709 13.2 43.043 ;
     RECT  29.712 44.437 31.2 47.603 ;
     RECT  15.96 47.269 17.088 47.363 ;
     RECT  15.96 47.363 17.76 47.701 ;
     RECT  16.776 47.701 17.76 49.525 ;
     RECT  24.312 47.845 25.824 48.131 ;
     RECT  19.224 48.035 19.56 48.419 ;
     RECT  24.312 48.131 25.848 49.477 ;
     RECT  35.112 48.179 35.352 49.477 ;
     RECT  18.912 48.419 19.56 49.525 ;
     RECT  15.768 48.515 16.752 49.477 ;
     RECT  24.312 49.477 26.112 49.525 ;
     RECT  30.024 49.525 31.296 51.708 ;
     RECT  32.184 49.525 33.456 51.708 ;
     RECT  29.4 49.703 29.568 50.725 ;
     RECT  34.344 49.703 35.616 51.708 ;
     RECT  27.864 50.725 29.136 51.708 ;
     RECT  27.912 51.708 28.224 51.792 ;
     RECT  28.344 51.708 28.656 51.792 ;
     RECT  28.776 51.708 29.088 51.792 ;
     RECT  30.072 51.708 30.384 51.792 ;
     RECT  30.504 51.708 30.816 51.792 ;
     RECT  30.936 51.708 31.248 51.792 ;
     RECT  32.232 51.708 32.544 51.792 ;
     RECT  32.664 51.708 32.976 51.792 ;
     RECT  33.096 51.708 33.408 51.792 ;
     RECT  34.392 51.708 34.704 51.792 ;
     RECT  34.824 51.708 35.136 51.792 ;
     RECT  35.256 51.708 35.568 51.792 ;
  END
END dsfd_vm_static_read_v3_p
END LIBRARY
